One B-rep face of a CAD part: STEP entity #1094.
In plain terms, the planar face has unit normal (0, 1, 0).
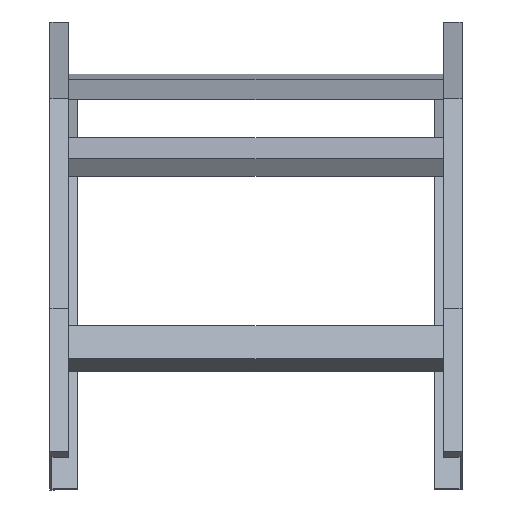
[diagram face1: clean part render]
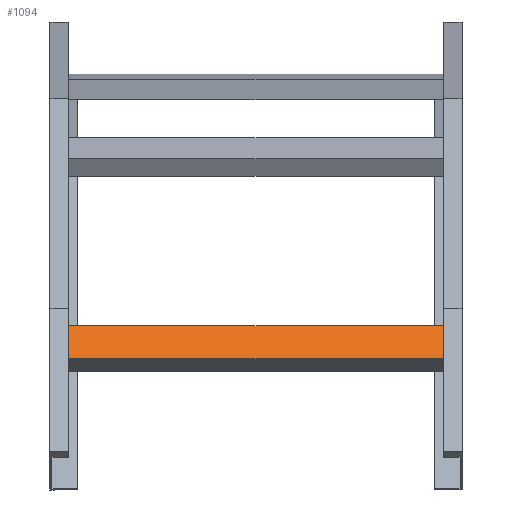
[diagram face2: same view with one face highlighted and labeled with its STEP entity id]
Its self-contained STEP definition (entity closure, numbers rounded to 3 decimals):
#35 = ORIENTED_EDGE ( 'NONE', *, *, #1507, .T. ) ;
#40 = CARTESIAN_POINT ( 'NONE',  ( 198., 20., 20.25 ) ) ;
#57 = ORIENTED_EDGE ( 'NONE', *, *, #1000, .F. ) ;
#232 = DIRECTION ( 'NONE',  ( -1., 0., 0. ) ) ;
#241 = LINE ( 'NONE', #769, #651 ) ;
#354 = EDGE_CURVE ( 'NONE', #652, #1472, #944, .T. ) ;
#517 = CARTESIAN_POINT ( 'NONE',  ( 198., 20., 20.25 ) ) ;
#570 = CARTESIAN_POINT ( 'NONE',  ( 198., 20., 20.25 ) ) ;
#573 = CARTESIAN_POINT ( 'NONE',  ( -198., 20., 20.25 ) ) ;
#580 = VECTOR ( 'NONE', #1641, 1000. ) ;
#620 = EDGE_LOOP ( 'NONE', ( #35, #1455, #57, #727 ) ) ;
#651 = VECTOR ( 'NONE', #1283, 1000. ) ;
#652 = VERTEX_POINT ( 'NONE', #711 ) ;
#711 = CARTESIAN_POINT ( 'NONE',  ( 198., 20., -20.25 ) ) ;
#715 = VERTEX_POINT ( 'NONE', #1115 ) ;
#727 = ORIENTED_EDGE ( 'NONE', *, *, #354, .T. ) ;
#758 = LINE ( 'NONE', #570, #1086 ) ;
#769 = CARTESIAN_POINT ( 'NONE',  ( 198., 20., 20.25 ) ) ;
#944 = LINE ( 'NONE', #1088, #1184 ) ;
#990 = EDGE_CURVE ( 'NONE', #997, #715, #758, .T. ) ;
#997 = VERTEX_POINT ( 'NONE', #517 ) ;
#1000 = EDGE_CURVE ( 'NONE', #652, #997, #241, .T. ) ;
#1076 = DIRECTION ( 'NONE',  ( 0., -1., 0. ) ) ;
#1086 = VECTOR ( 'NONE', #232, 1000. ) ;
#1088 = CARTESIAN_POINT ( 'NONE',  ( 198., 20., -20.25 ) ) ;
#1094 = ADVANCED_FACE ( 'NONE', ( #1399 ), #1487, .F. ) ;
#1097 = DIRECTION ( 'NONE',  ( 0., 0., -1. ) ) ;
#1115 = CARTESIAN_POINT ( 'NONE',  ( -198., 20., 20.25 ) ) ;
#1184 = VECTOR ( 'NONE', #1630, 1000. ) ;
#1256 = LINE ( 'NONE', #573, #580 ) ;
#1283 = DIRECTION ( 'NONE',  ( 0., 0., 1. ) ) ;
#1399 = FACE_OUTER_BOUND ( 'NONE', #620, .T. ) ;
#1455 = ORIENTED_EDGE ( 'NONE', *, *, #990, .F. ) ;
#1472 = VERTEX_POINT ( 'NONE', #1599 ) ;
#1487 = PLANE ( 'NONE',  #1681 ) ;
#1507 = EDGE_CURVE ( 'NONE', #1472, #715, #1256, .T. ) ;
#1599 = CARTESIAN_POINT ( 'NONE',  ( -198., 20., -20.25 ) ) ;
#1630 = DIRECTION ( 'NONE',  ( -1., 0., 0. ) ) ;
#1641 = DIRECTION ( 'NONE',  ( 0., 0., 1. ) ) ;
#1681 = AXIS2_PLACEMENT_3D ( 'NONE', #40, #1076, #1097 ) ;
